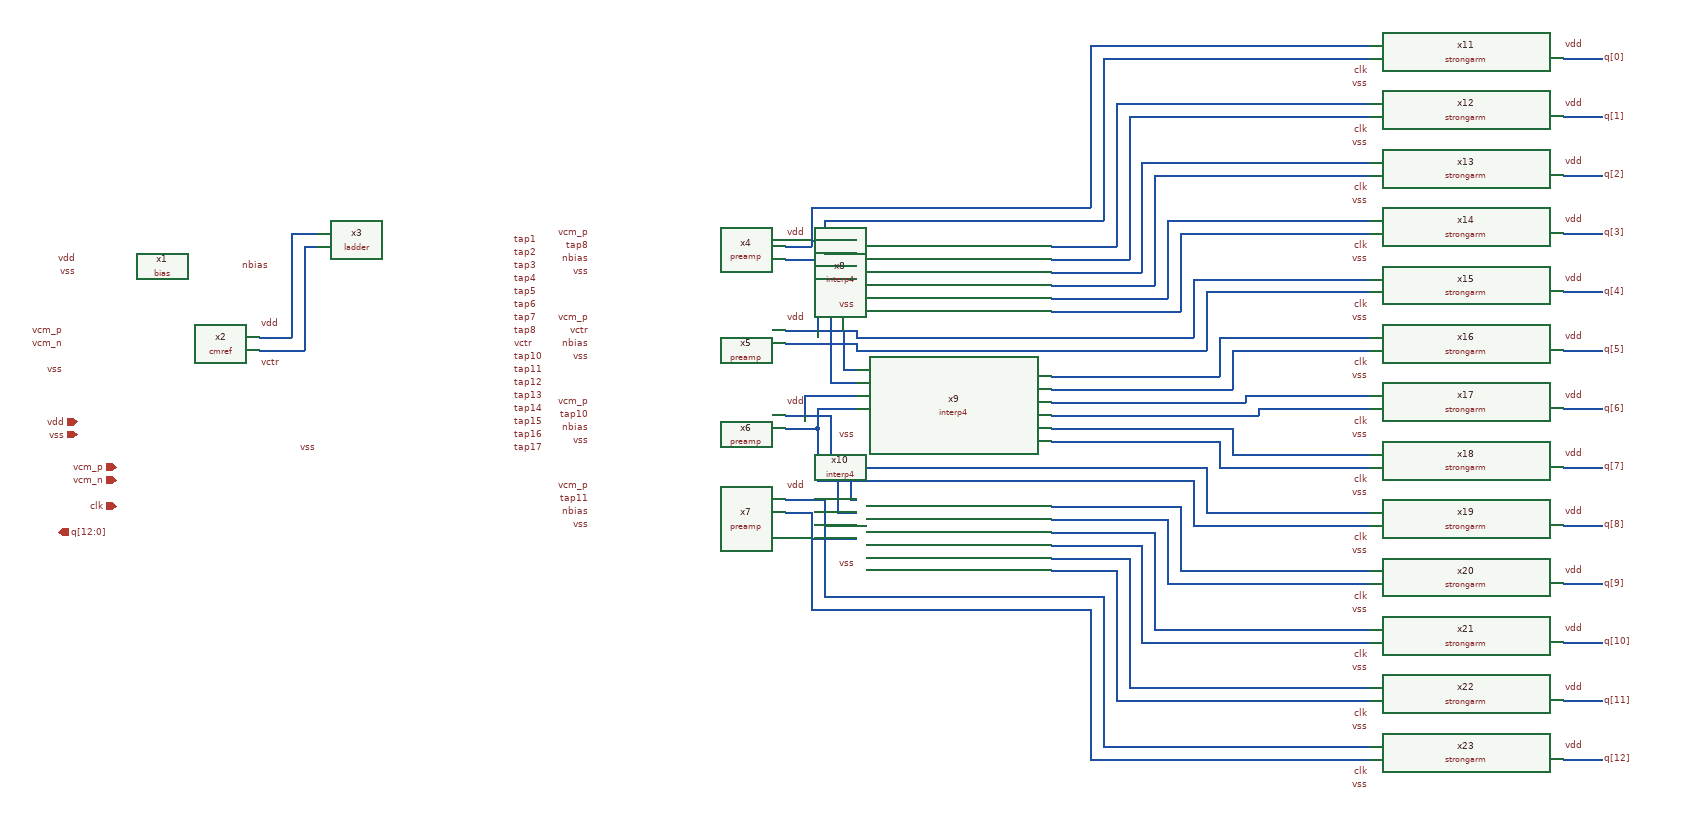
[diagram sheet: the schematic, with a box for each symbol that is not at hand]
v {xschem version=3.4.8RC file_version=1.3}
G {}
K {}
V {}
S {}
F {}
E {}
N 50 600 100 600 {lab=#net1}
N 100 440 100 600 {lab=#net1}
N 100 440 140 440 {lab=#net1}
N 120 460 140 460 {lab=#net2}
N 120 460 120 620 {lab=#net2}
N 50 620 120 620 {lab=#net2}
N 860 590 970 590 {lab=#net3}
N 970 590 970 600 {lab=#net3}
N 970 600 1330 600 {lab=#net3}
N 860 610 970 610 {lab=#net4}
N 970 610 970 620 {lab=#net4}
N 970 620 1330 620 {lab=#net4}
N 860 720 930 720 {lab=#net5}
N 930 720 930 800 {lab=#net5}
N 930 800 1330 800 {lab=#net5}
N 860 740 910 740 {lab=#net6}
N 910 740 910 820 {lab=#net6}
N 910 820 1330 820 {lab=#net6}
N 860 460 900 460 {lab=#net7}
N 860 480 920 480 {lab=#net8}
N 920 420 920 480 {lab=#net8}
N 920 420 1330 420 {lab=#net8}
N 900 400 900 460 {lab=#net7}
N 900 400 1330 400 {lab=#net7}
N 860 870 900 870 {lab=#net9}
N 900 870 900 980 {lab=#net9}
N 860 850 920 850 {lab=#net10}
N 920 850 920 1000 {lab=#net10}
N 920 1000 1330 1000 {lab=#net10}
N 900 980 900 1020 {lab=#net9}
N 900 1020 1330 1020 {lab=#net9}
N 900 450 970 450 {lab=#net7}
N 920 470 970 470 {lab=#net8}
N 930 510 970 510 {lab=#net4}
N 930 510 930 610 {lab=#net4}
N 910 490 970 490 {lab=#net3}
N 910 490 910 590 {lab=#net3}
N 930 610 930 670 {lab=#net4}
N 930 670 970 670 {lab=#net4}
N 950 650 970 650 {lab=#net3}
N 950 590 950 650 {lab=#net3}
N 910 710 970 710 {lab=#net6}
N 910 710 910 740 {lab=#net6}
N 890 690 970 690 {lab=#net5}
N 890 690 890 720 {lab=#net5}
N 960 850 970 850 {lab=#net5}
N 960 800 960 850 {lab=#net5}
N 940 870 970 870 {lab=#net6}
N 940 820 940 870 {lab=#net6}
N 920 890 970 890 {lab=#net10}
N 900 910 970 910 {lab=#net9}
N 2060 170 2120 170 {lab=q[0]}
N 2060 260 2120 260 {lab=q[0]}
N 2060 350 2120 350 {lab=q[0]}
N 2060 440 2120 440 {lab=q[0]}
N 2060 530 2120 530 {lab=q[0]}
N 2060 620 2120 620 {lab=q[0]}
N 2060 710 2120 710 {lab=q[0]}
N 2060 800 2120 800 {lab=q[0]}
N 2060 890 2120 890 {lab=q[0]}
N 2060 980 2120 980 {lab=q[0]}
N 2060 1070 2120 1070 {lab=q[0]}
N 2060 1160 2120 1160 {lab=q[0]}
N 2060 1250 2120 1250 {lab=q[0]}
N 1330 150 1330 400 {lab=#net7}
N 1330 150 1760 150 {lab=#net7}
N 1330 420 1350 420 {lab=#net8}
N 1350 170 1350 420 {lab=#net8}
N 1350 170 1760 170 {lab=#net8}
N 1370 240 1760 240 {lab=#net11}
N 1370 240 1370 460 {lab=#net11}
N 1270 460 1370 460 {lab=#net11}
N 1270 480 1390 480 {lab=#net12}
N 1390 260 1390 480 {lab=#net12}
N 1390 260 1760 260 {lab=#net12}
N 1410 330 1760 330 {lab=#net13}
N 1410 330 1410 500 {lab=#net13}
N 1270 500 1410 500 {lab=#net13}
N 1270 520 1430 520 {lab=#net14}
N 1430 350 1430 520 {lab=#net14}
N 1430 350 1760 350 {lab=#net14}
N 1450 420 1760 420 {lab=#net15}
N 1450 420 1450 540 {lab=#net15}
N 1270 540 1450 540 {lab=#net15}
N 1270 560 1460 560 {lab=#net16}
N 1460 560 1470 560 {lab=#net16}
N 1470 440 1470 560 {lab=#net16}
N 1470 440 1760 440 {lab=#net16}
N 1490 510 1760 510 {lab=#net3}
N 1490 510 1490 600 {lab=#net3}
N 1330 600 1490 600 {lab=#net3}
N 1330 620 1510 620 {lab=#net4}
N 1510 530 1510 620 {lab=#net4}
N 1510 530 1760 530 {lab=#net4}
N 1270 660 1530 660 {lab=#net17}
N 1530 600 1530 660 {lab=#net17}
N 1530 600 1760 600 {lab=#net17}
N 1550 620 1760 620 {lab=#net18}
N 1550 620 1550 680 {lab=#net18}
N 1270 680 1550 680 {lab=#net18}
N 1270 700 1570 700 {lab=#net19}
N 1570 690 1570 700 {lab=#net19}
N 1570 690 1760 690 {lab=#net19}
N 1590 710 1760 710 {lab=#net20}
N 1270 720 1590 720 {lab=#net20}
N 1590 710 1590 720 {lab=#net20}
N 1330 1020 1330 1250 {lab=#net9}
N 1330 1250 1760 1250 {lab=#net9}
N 1330 1000 1350 1000 {lab=#net10}
N 1350 1000 1350 1230 {lab=#net10}
N 1350 1230 1760 1230 {lab=#net10}
N 1270 960 1370 960 {lab=#net21}
N 1370 960 1370 1160 {lab=#net21}
N 1370 1160 1760 1160 {lab=#net21}
N 1390 1140 1760 1140 {lab=#net22}
N 1390 940 1390 1140 {lab=#net22}
N 1270 940 1390 940 {lab=#net22}
N 1270 920 1410 920 {lab=#net23}
N 1410 920 1410 1070 {lab=#net23}
N 1410 1070 1760 1070 {lab=#net23}
N 1430 1050 1760 1050 {lab=#net24}
N 1430 910 1430 1050 {lab=#net24}
N 1270 900 1430 900 {lab=#net24}
N 1430 900 1430 910 {lab=#net24}
N 1270 880 1450 880 {lab=#net25}
N 1450 880 1450 980 {lab=#net25}
N 1450 980 1760 980 {lab=#net25}
N 1470 960 1760 960 {lab=#net26}
N 1470 870 1470 960 {lab=#net26}
N 1470 860 1470 870 {lab=#net26}
N 1270 860 1470 860 {lab=#net26}
N 1330 820 1490 820 {lab=#net6}
N 1490 820 1490 890 {lab=#net6}
N 1490 890 1760 890 {lab=#net6}
N 1330 800 1510 800 {lab=#net5}
N 1510 800 1510 870 {lab=#net5}
N 1510 870 1760 870 {lab=#net5}
N 1270 760 1530 760 {lab=#net27}
N 1530 760 1530 800 {lab=#net27}
N 1530 800 1760 800 {lab=#net27}
N 1270 740 1550 740 {lab=#net28}
N 1550 740 1550 780 {lab=#net28}
N 1550 780 1760 780 {lab=#net28}
C {title.sym} -80 -10 0 0 {name=l2 author="Pranav Vadde"}
C {/headless/eda/designs/gf180_flash_adc/bias.sym} -100 490 0 0 {name=x1}
C {lab_wire.sym} -230 480 0 0 {name=p13 sig_type=std_logic lab=vdd}
C {lab_wire.sym} -230 500 0 0 {name=p1 sig_type=std_logic lab=vss}
C {lab_wire.sym} 20 490 0 1 {name=p2 sig_type=std_logic lab=nbias
}
C {/headless/eda/designs/gf180_flash_adc/cmref.sym} -100 620 0 0 {name=x2}
C {lab_wire.sym} 50 580 0 1 {name=p3 sig_type=std_logic lab=vdd
}
C {lab_wire.sym} 50 640 0 1 {name=p6 sig_type=std_logic lab=vctr
}
C {lab_wire.sym} -250 590 0 0 {name=p7 sig_type=std_logic lab=vcm_p}
C {lab_wire.sym} -250 610 0 0 {name=p8 sig_type=std_logic lab=vcm_n}
C {lab_wire.sym} -250 650 0 0 {name=p9 sig_type=std_logic lab=vss}
C {/headless/eda/designs/gf180_flash_adc/ladder.sym} 290 610 0 0 {name=x3}
C {lab_wire.sym} 440 610 0 1 {name=p10 sig_type=std_logic lab=vctr
}
C {lab_wire.sym} 140 770 0 0 {name=p4 sig_type=std_logic lab=vss}
C {lab_wire.sym} 440 450 0 1 {name=p5 sig_type=std_logic lab=tap1
}
C {lab_wire.sym} 440 470 0 1 {name=p11 sig_type=std_logic lab=tap2
}
C {lab_wire.sym} 440 490 0 1 {name=p12 sig_type=std_logic lab=tap3
}
C {lab_wire.sym} 440 510 0 1 {name=p14 sig_type=std_logic lab=tap4
}
C {lab_wire.sym} 440 530 0 1 {name=p15 sig_type=std_logic lab=tap5
}
C {lab_wire.sym} 440 550 0 1 {name=p16 sig_type=std_logic lab=tap6
}
C {lab_wire.sym} 440 570 0 1 {name=p17 sig_type=std_logic lab=tap7
}
C {lab_wire.sym} 440 590 0 1 {name=p18 sig_type=std_logic lab=tap8
}
C {lab_wire.sym} 440 630 0 1 {name=p19 sig_type=std_logic lab=tap10
}
C {lab_wire.sym} 440 650 0 1 {name=p20 sig_type=std_logic lab=tap11

}
C {lab_wire.sym} 440 670 0 1 {name=p21 sig_type=std_logic lab=tap12
}
C {lab_wire.sym} 440 690 0 1 {name=p22 sig_type=std_logic lab=tap13
}
C {lab_wire.sym} 440 710 0 1 {name=p23 sig_type=std_logic lab=tap14
}
C {lab_wire.sym} 440 730 0 1 {name=p24 sig_type=std_logic lab=tap15
}
C {lab_wire.sym} 440 750 0 1 {name=p25 sig_type=std_logic lab=tap16
}
C {lab_wire.sym} 440 770 0 1 {name=p26 sig_type=std_logic lab=tap17
}
C {/headless/eda/designs/gf180_flash_adc/preamp.sym} 710 470 0 0 {name=x4}
C {lab_wire.sym} 860 440 0 1 {name=p27 sig_type=std_logic lab=vdd
}
C {lab_wire.sym} 560 500 0 0 {name=p28 sig_type=std_logic lab=vss}
C {lab_wire.sym} 560 480 0 0 {name=p29 sig_type=std_logic lab=nbias
}
C {lab_wire.sym} 560 460 0 0 {name=p30 sig_type=std_logic lab=tap8
}
C {lab_wire.sym} 560 440 0 0 {name=p31 sig_type=std_logic lab=vcm_p}
C {/headless/eda/designs/gf180_flash_adc/preamp.sym} 710 600 0 0 {name=x5}
C {lab_wire.sym} 860 570 0 1 {name=p32 sig_type=std_logic lab=vdd
}
C {lab_wire.sym} 560 630 0 0 {name=p33 sig_type=std_logic lab=vss}
C {lab_wire.sym} 560 610 0 0 {name=p34 sig_type=std_logic lab=nbias
}
C {lab_wire.sym} 560 590 0 0 {name=p35 sig_type=std_logic lab=vctr
}
C {lab_wire.sym} 560 570 0 0 {name=p36 sig_type=std_logic lab=vcm_p}
C {/headless/eda/designs/gf180_flash_adc/preamp.sym} 710 730 0 0 {name=x6}
C {lab_wire.sym} 860 700 0 1 {name=p37 sig_type=std_logic lab=vdd
}
C {lab_wire.sym} 560 760 0 0 {name=p38 sig_type=std_logic lab=vss}
C {lab_wire.sym} 560 740 0 0 {name=p39 sig_type=std_logic lab=nbias
}
C {lab_wire.sym} 560 720 0 0 {name=p40 sig_type=std_logic lab=tap10
}
C {lab_wire.sym} 560 700 0 0 {name=p41 sig_type=std_logic lab=vcm_p}
C {/headless/eda/designs/gf180_flash_adc/preamp.sym} 710 860 0 0 {name=x7}
C {lab_wire.sym} 860 830 0 1 {name=p42 sig_type=std_logic lab=vdd
}
C {lab_wire.sym} 560 890 0 0 {name=p43 sig_type=std_logic lab=vss}
C {lab_wire.sym} 560 870 0 0 {name=p44 sig_type=std_logic lab=nbias
}
C {lab_wire.sym} 560 850 0 0 {name=p45 sig_type=std_logic lab=tap11
}
C {lab_wire.sym} 560 830 0 0 {name=p46 sig_type=std_logic lab=vcm_p}
C {/headless/eda/designs/gf180_flash_adc/interp4.sym} 1120 510 0 0 {name=x8}
C {lab_wire.sym} 970 550 0 0 {name=p47 sig_type=std_logic lab=vss}
C {/headless/eda/designs/gf180_flash_adc/interp4.sym} 1120 710 0 0 {name=x9}
C {/headless/eda/designs/gf180_flash_adc/interp4.sym} 1120 910 0 0 {name=x10}
C {iopin.sym} -230 730 0 0 {name=pvdd lab=vdd}
C {iopin.sym} -230 750 0 0 {name=pvss lab=vss}
C {ipin.sym} -170 800 0 0 {name=p48 lab=vcm_p}
C {ipin.sym} -170 820 0 0 {name=p49 lab=vcm_n}
C {lab_wire.sym} 970 750 0 0 {name=p50 sig_type=std_logic lab=vss}
C {lab_wire.sym} 970 950 0 0 {name=p51 sig_type=std_logic lab=vss}
C {ipin.sym} -170 860 0 0 {name=p52 lab=clk}
C {/headless/eda/designs/gf180_flash_adc/strongarm.sym} 1910 180 0 0 {name=x11}
C {/headless/eda/designs/gf180_flash_adc/strongarm.sym} 1910 270 0 0 {name=x12}
C {lab_wire.sym} 1760 300 0 0 {name=p53 sig_type=std_logic lab=vss}
C {lab_wire.sym} 1760 210 0 0 {name=p54 sig_type=std_logic lab=vss}
C {lab_wire.sym} 1760 190 0 0 {name=p56 sig_type=std_logic lab=clk}
C {lab_wire.sym} 2060 150 0 1 {name=p57 sig_type=std_logic lab=vdd}
C {lab_wire.sym} 2060 240 0 1 {name=p58 sig_type=std_logic lab=vdd}
C {lab_wire.sym} 2120 170 0 1 {name=p59 sig_type=std_logic lab=q[0]}
C {lab_wire.sym} 2120 260 0 1 {name=p60 sig_type=std_logic lab=q[1]}
C {/headless/eda/designs/gf180_flash_adc/strongarm.sym} 1910 360 0 0 {name=x13}
C {/headless/eda/designs/gf180_flash_adc/strongarm.sym} 1910 450 0 0 {name=x14}
C {lab_wire.sym} 1760 480 0 0 {name=p61 sig_type=std_logic lab=vss}
C {lab_wire.sym} 1760 390 0 0 {name=p62 sig_type=std_logic lab=vss}
C {lab_wire.sym} 2060 330 0 1 {name=p65 sig_type=std_logic lab=vdd}
C {lab_wire.sym} 2060 420 0 1 {name=p66 sig_type=std_logic lab=vdd}
C {lab_wire.sym} 2120 350 0 1 {name=p67 sig_type=std_logic lab=q[2]}
C {lab_wire.sym} 2120 440 0 1 {name=p68 sig_type=std_logic lab=q[3]}
C {/headless/eda/designs/gf180_flash_adc/strongarm.sym} 1910 540 0 0 {name=x15}
C {/headless/eda/designs/gf180_flash_adc/strongarm.sym} 1910 630 0 0 {name=x16}
C {lab_wire.sym} 1760 660 0 0 {name=p69 sig_type=std_logic lab=vss}
C {lab_wire.sym} 1760 570 0 0 {name=p70 sig_type=std_logic lab=vss}
C {lab_wire.sym} 2060 510 0 1 {name=p73 sig_type=std_logic lab=vdd}
C {lab_wire.sym} 2060 600 0 1 {name=p74 sig_type=std_logic lab=vdd}
C {lab_wire.sym} 2120 530 0 1 {name=p75 sig_type=std_logic lab=q[4]}
C {lab_wire.sym} 2120 620 0 1 {name=p76 sig_type=std_logic lab=q[5]}
C {/headless/eda/designs/gf180_flash_adc/strongarm.sym} 1910 720 0 0 {name=x17}
C {/headless/eda/designs/gf180_flash_adc/strongarm.sym} 1910 810 0 0 {name=x18}
C {lab_wire.sym} 1760 840 0 0 {name=p77 sig_type=std_logic lab=vss}
C {lab_wire.sym} 1760 750 0 0 {name=p78 sig_type=std_logic lab=vss}
C {lab_wire.sym} 2060 690 0 1 {name=p81 sig_type=std_logic lab=vdd}
C {lab_wire.sym} 2060 780 0 1 {name=p82 sig_type=std_logic lab=vdd}
C {lab_wire.sym} 2120 710 0 1 {name=p83 sig_type=std_logic lab=q[6]}
C {lab_wire.sym} 2120 800 0 1 {name=p84 sig_type=std_logic lab=q[7]}
C {/headless/eda/designs/gf180_flash_adc/strongarm.sym} 1910 900 0 0 {name=x19}
C {/headless/eda/designs/gf180_flash_adc/strongarm.sym} 1910 990 0 0 {name=x20}
C {lab_wire.sym} 1760 1020 0 0 {name=p85 sig_type=std_logic lab=vss}
C {lab_wire.sym} 1760 930 0 0 {name=p86 sig_type=std_logic lab=vss}
C {lab_wire.sym} 2060 870 0 1 {name=p89 sig_type=std_logic lab=vdd}
C {lab_wire.sym} 2060 960 0 1 {name=p90 sig_type=std_logic lab=vdd}
C {lab_wire.sym} 2120 890 0 1 {name=p91 sig_type=std_logic lab=q[8]}
C {lab_wire.sym} 2120 980 0 1 {name=p92 sig_type=std_logic lab=q[9]}
C {/headless/eda/designs/gf180_flash_adc/strongarm.sym} 1910 1080 0 0 {name=x21}
C {/headless/eda/designs/gf180_flash_adc/strongarm.sym} 1910 1170 0 0 {name=x22}
C {lab_wire.sym} 1760 1200 0 0 {name=p93 sig_type=std_logic lab=vss}
C {lab_wire.sym} 1760 1110 0 0 {name=p94 sig_type=std_logic lab=vss}
C {lab_wire.sym} 2060 1050 0 1 {name=p97 sig_type=std_logic lab=vdd}
C {lab_wire.sym} 2060 1140 0 1 {name=p98 sig_type=std_logic lab=vdd}
C {lab_wire.sym} 2120 1070 0 1 {name=p99 sig_type=std_logic lab=q[10]}
C {lab_wire.sym} 2120 1160 0 1 {name=p100 sig_type=std_logic lab=q[11]}
C {/headless/eda/designs/gf180_flash_adc/strongarm.sym} 1910 1260 0 0 {name=x23}
C {lab_wire.sym} 1760 1290 0 0 {name=p101 sig_type=std_logic lab=vss}
C {lab_wire.sym} 1760 1270 0 0 {name=p102 sig_type=std_logic lab=clk}
C {lab_wire.sym} 2060 1230 0 1 {name=p103 sig_type=std_logic lab=vdd}
C {lab_wire.sym} 2120 1250 0 1 {name=p104 sig_type=std_logic lab=q[12]}
C {lab_wire.sym} 1760 1180 0 0 {name=p55 sig_type=std_logic lab=clk}
C {lab_wire.sym} 1760 1090 0 0 {name=p63 sig_type=std_logic lab=clk}
C {lab_wire.sym} 1760 1000 0 0 {name=p64 sig_type=std_logic lab=clk}
C {lab_wire.sym} 1760 910 0 0 {name=p71 sig_type=std_logic lab=clk}
C {lab_wire.sym} 1760 820 0 0 {name=p72 sig_type=std_logic lab=clk}
C {lab_wire.sym} 1760 730 0 0 {name=p79 sig_type=std_logic lab=clk}
C {lab_wire.sym} 1760 640 0 0 {name=p80 sig_type=std_logic lab=clk}
C {lab_wire.sym} 1760 550 0 0 {name=p87 sig_type=std_logic lab=clk}
C {lab_wire.sym} 1760 460 0 0 {name=p88 sig_type=std_logic lab=clk}
C {lab_wire.sym} 1760 370 0 0 {name=p95 sig_type=std_logic lab=clk}
C {lab_wire.sym} 1760 280 0 0 {name=p96 sig_type=std_logic lab=clk}
C {opin.sym} -260 900 0 0 {name=p106 lab=q[12:0]}
